VERSION 5.7 ;
  NOWIREEXTENSIONATPIN ON ;
  DIVIDERCHAR "/" ;
  BUSBITCHARS "[]" ;
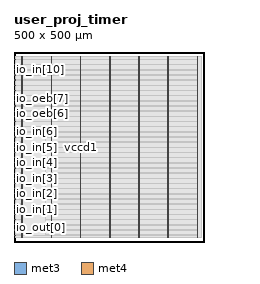
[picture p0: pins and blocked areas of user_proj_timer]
MACRO user_proj_timer
  CLASS BLOCK ;
  FOREIGN user_proj_timer ;
  ORIGIN 0.000 0.000 ;
  SIZE 500.000 BY 500.000 ;
  PIN io_in[0]
    DIRECTION INPUT ;
    USE SIGNAL ;
    ANTENNAGATEAREA 0.126000 ;
    PORT
      LAYER met3 ;
        RECT 0.000 44.920 4.000 45.520 ;
    END
  END io_in[0]
  PIN io_in[10]
    DIRECTION INPUT ;
    USE SIGNAL ;
    PORT
      LAYER met3 ;
        RECT 0.000 452.920 4.000 453.520 ;
    END
  END io_in[10]
  PIN io_in[1]
    DIRECTION INPUT ;
    USE SIGNAL ;
    ANTENNAGATEAREA 0.196500 ;
    PORT
      LAYER met3 ;
        RECT 0.000 85.720 4.000 86.320 ;
    END
  END io_in[1]
  PIN io_in[2]
    DIRECTION INPUT ;
    USE SIGNAL ;
    PORT
      LAYER met3 ;
        RECT 0.000 126.520 4.000 127.120 ;
    END
  END io_in[2]
  PIN io_in[3]
    DIRECTION INPUT ;
    USE SIGNAL ;
    PORT
      LAYER met3 ;
        RECT 0.000 167.320 4.000 167.920 ;
    END
  END io_in[3]
  PIN io_in[4]
    DIRECTION INPUT ;
    USE SIGNAL ;
    PORT
      LAYER met3 ;
        RECT 0.000 208.120 4.000 208.720 ;
    END
  END io_in[4]
  PIN io_in[5]
    DIRECTION INPUT ;
    USE SIGNAL ;
    PORT
      LAYER met3 ;
        RECT 0.000 248.920 4.000 249.520 ;
    END
  END io_in[5]
  PIN io_in[6]
    DIRECTION INPUT ;
    USE SIGNAL ;
    PORT
      LAYER met3 ;
        RECT 0.000 289.720 4.000 290.320 ;
    END
  END io_in[6]
  PIN io_in[7]
    DIRECTION INPUT ;
    USE SIGNAL ;
    PORT
      LAYER met3 ;
        RECT 0.000 330.520 4.000 331.120 ;
    END
  END io_in[7]
  PIN io_in[8]
    DIRECTION INPUT ;
    USE SIGNAL ;
    PORT
      LAYER met3 ;
        RECT 0.000 371.320 4.000 371.920 ;
    END
  END io_in[8]
  PIN io_in[9]
    DIRECTION INPUT ;
    USE SIGNAL ;
    PORT
      LAYER met3 ;
        RECT 0.000 412.120 4.000 412.720 ;
    END
  END io_in[9]
  PIN io_oeb[0]
    DIRECTION OUTPUT ;
    USE SIGNAL ;
    PORT
      LAYER met3 ;
        RECT 0.000 72.120 4.000 72.720 ;
    END
  END io_oeb[0]
  PIN io_oeb[10]
    DIRECTION OUTPUT ;
    USE SIGNAL ;
    PORT
      LAYER met3 ;
        RECT 0.000 480.120 4.000 480.720 ;
    END
  END io_oeb[10]
  PIN io_oeb[1]
    DIRECTION OUTPUT ;
    USE SIGNAL ;
    PORT
      LAYER met3 ;
        RECT 0.000 112.920 4.000 113.520 ;
    END
  END io_oeb[1]
  PIN io_oeb[2]
    DIRECTION OUTPUT ;
    USE SIGNAL ;
    PORT
      LAYER met3 ;
        RECT 0.000 153.720 4.000 154.320 ;
    END
  END io_oeb[2]
  PIN io_oeb[3]
    DIRECTION OUTPUT ;
    USE SIGNAL ;
    PORT
      LAYER met3 ;
        RECT 0.000 194.520 4.000 195.120 ;
    END
  END io_oeb[3]
  PIN io_oeb[4]
    DIRECTION OUTPUT ;
    USE SIGNAL ;
    PORT
      LAYER met3 ;
        RECT 0.000 235.320 4.000 235.920 ;
    END
  END io_oeb[4]
  PIN io_oeb[5]
    DIRECTION OUTPUT ;
    USE SIGNAL ;
    PORT
      LAYER met3 ;
        RECT 0.000 276.120 4.000 276.720 ;
    END
  END io_oeb[5]
  PIN io_oeb[6]
    DIRECTION OUTPUT ;
    USE SIGNAL ;
    PORT
      LAYER met3 ;
        RECT 0.000 316.920 4.000 317.520 ;
    END
  END io_oeb[6]
  PIN io_oeb[7]
    DIRECTION OUTPUT ;
    USE SIGNAL ;
    PORT
      LAYER met3 ;
        RECT 0.000 357.720 4.000 358.320 ;
    END
  END io_oeb[7]
  PIN io_oeb[8]
    DIRECTION OUTPUT ;
    USE SIGNAL ;
    PORT
      LAYER met3 ;
        RECT 0.000 398.520 4.000 399.120 ;
    END
  END io_oeb[8]
  PIN io_oeb[9]
    DIRECTION OUTPUT ;
    USE SIGNAL ;
    PORT
      LAYER met3 ;
        RECT 0.000 439.320 4.000 439.920 ;
    END
  END io_oeb[9]
  PIN io_out[0]
    DIRECTION OUTPUT ;
    USE SIGNAL ;
    ANTENNADIFFAREA 0.445500 ;
    PORT
      LAYER met3 ;
        RECT 0.000 58.520 4.000 59.120 ;
    END
  END io_out[0]
  PIN io_out[10]
    DIRECTION OUTPUT ;
    USE SIGNAL ;
    ANTENNADIFFAREA 0.445500 ;
    PORT
      LAYER met3 ;
        RECT 0.000 466.520 4.000 467.120 ;
    END
  END io_out[10]
  PIN io_out[1]
    DIRECTION OUTPUT ;
    USE SIGNAL ;
    ANTENNADIFFAREA 0.445500 ;
    PORT
      LAYER met3 ;
        RECT 0.000 99.320 4.000 99.920 ;
    END
  END io_out[1]
  PIN io_out[2]
    DIRECTION OUTPUT ;
    USE SIGNAL ;
    ANTENNADIFFAREA 0.445500 ;
    PORT
      LAYER met3 ;
        RECT 0.000 140.120 4.000 140.720 ;
    END
  END io_out[2]
  PIN io_out[3]
    DIRECTION OUTPUT ;
    USE SIGNAL ;
    ANTENNADIFFAREA 0.445500 ;
    PORT
      LAYER met3 ;
        RECT 0.000 180.920 4.000 181.520 ;
    END
  END io_out[3]
  PIN io_out[4]
    DIRECTION OUTPUT ;
    USE SIGNAL ;
    ANTENNADIFFAREA 0.445500 ;
    PORT
      LAYER met3 ;
        RECT 0.000 221.720 4.000 222.320 ;
    END
  END io_out[4]
  PIN io_out[5]
    DIRECTION OUTPUT ;
    USE SIGNAL ;
    ANTENNADIFFAREA 0.445500 ;
    PORT
      LAYER met3 ;
        RECT 0.000 262.520 4.000 263.120 ;
    END
  END io_out[5]
  PIN io_out[6]
    DIRECTION OUTPUT ;
    USE SIGNAL ;
    ANTENNADIFFAREA 0.445500 ;
    PORT
      LAYER met3 ;
        RECT 0.000 303.320 4.000 303.920 ;
    END
  END io_out[6]
  PIN io_out[7]
    DIRECTION OUTPUT ;
    USE SIGNAL ;
    ANTENNADIFFAREA 0.445500 ;
    PORT
      LAYER met3 ;
        RECT 0.000 344.120 4.000 344.720 ;
    END
  END io_out[7]
  PIN io_out[8]
    DIRECTION OUTPUT ;
    USE SIGNAL ;
    ANTENNADIFFAREA 0.445500 ;
    PORT
      LAYER met3 ;
        RECT 0.000 384.920 4.000 385.520 ;
    END
  END io_out[8]
  PIN io_out[9]
    DIRECTION OUTPUT ;
    USE SIGNAL ;
    ANTENNADIFFAREA 0.445500 ;
    PORT
      LAYER met3 ;
        RECT 0.000 425.720 4.000 426.320 ;
    END
  END io_out[9]
  PIN vccd1
    DIRECTION INOUT ;
    USE POWER ;
    PORT
      LAYER met4 ;
        RECT 21.040 10.640 22.640 487.120 ;
    END
    PORT
      LAYER met4 ;
        RECT 174.640 10.640 176.240 487.120 ;
    END
    PORT
      LAYER met4 ;
        RECT 328.240 10.640 329.840 487.120 ;
    END
    PORT
      LAYER met4 ;
        RECT 481.840 10.640 483.440 487.120 ;
    END
  END vccd1
  PIN vssd1
    DIRECTION INOUT ;
    USE GROUND ;
    PORT
      LAYER met4 ;
        RECT 97.840 10.640 99.440 487.120 ;
    END
    PORT
      LAYER met4 ;
        RECT 251.440 10.640 253.040 487.120 ;
    END
    PORT
      LAYER met4 ;
        RECT 405.040 10.640 406.640 487.120 ;
    END
  END vssd1
  PIN wb_clk_i
    DIRECTION INPUT ;
    USE SIGNAL ;
    ANTENNAGATEAREA 0.852000 ;
    ANTENNADIFFAREA 0.434700 ;
    PORT
      LAYER met3 ;
        RECT 0.000 17.720 4.000 18.320 ;
    END
  END wb_clk_i
  PIN wb_rst_i
    DIRECTION INPUT ;
    USE SIGNAL ;
    ANTENNAGATEAREA 0.159000 ;
    PORT
      LAYER met3 ;
        RECT 0.000 31.320 4.000 31.920 ;
    END
  END wb_rst_i
  OBS
      LAYER nwell ;
        RECT 5.330 10.795 494.230 487.070 ;
      LAYER li1 ;
        RECT 5.520 10.795 494.040 486.965 ;
      LAYER met1 ;
        RECT 4.210 10.640 494.040 487.120 ;
      LAYER met2 ;
        RECT 4.230 10.695 483.410 487.065 ;
      LAYER met3 ;
        RECT 3.990 481.120 483.430 487.045 ;
        RECT 4.400 479.720 483.430 481.120 ;
        RECT 3.990 467.520 483.430 479.720 ;
        RECT 4.400 466.120 483.430 467.520 ;
        RECT 3.990 453.920 483.430 466.120 ;
        RECT 4.400 452.520 483.430 453.920 ;
        RECT 3.990 440.320 483.430 452.520 ;
        RECT 4.400 438.920 483.430 440.320 ;
        RECT 3.990 426.720 483.430 438.920 ;
        RECT 4.400 425.320 483.430 426.720 ;
        RECT 3.990 413.120 483.430 425.320 ;
        RECT 4.400 411.720 483.430 413.120 ;
        RECT 3.990 399.520 483.430 411.720 ;
        RECT 4.400 398.120 483.430 399.520 ;
        RECT 3.990 385.920 483.430 398.120 ;
        RECT 4.400 384.520 483.430 385.920 ;
        RECT 3.990 372.320 483.430 384.520 ;
        RECT 4.400 370.920 483.430 372.320 ;
        RECT 3.990 358.720 483.430 370.920 ;
        RECT 4.400 357.320 483.430 358.720 ;
        RECT 3.990 345.120 483.430 357.320 ;
        RECT 4.400 343.720 483.430 345.120 ;
        RECT 3.990 331.520 483.430 343.720 ;
        RECT 4.400 330.120 483.430 331.520 ;
        RECT 3.990 317.920 483.430 330.120 ;
        RECT 4.400 316.520 483.430 317.920 ;
        RECT 3.990 304.320 483.430 316.520 ;
        RECT 4.400 302.920 483.430 304.320 ;
        RECT 3.990 290.720 483.430 302.920 ;
        RECT 4.400 289.320 483.430 290.720 ;
        RECT 3.990 277.120 483.430 289.320 ;
        RECT 4.400 275.720 483.430 277.120 ;
        RECT 3.990 263.520 483.430 275.720 ;
        RECT 4.400 262.120 483.430 263.520 ;
        RECT 3.990 249.920 483.430 262.120 ;
        RECT 4.400 248.520 483.430 249.920 ;
        RECT 3.990 236.320 483.430 248.520 ;
        RECT 4.400 234.920 483.430 236.320 ;
        RECT 3.990 222.720 483.430 234.920 ;
        RECT 4.400 221.320 483.430 222.720 ;
        RECT 3.990 209.120 483.430 221.320 ;
        RECT 4.400 207.720 483.430 209.120 ;
        RECT 3.990 195.520 483.430 207.720 ;
        RECT 4.400 194.120 483.430 195.520 ;
        RECT 3.990 181.920 483.430 194.120 ;
        RECT 4.400 180.520 483.430 181.920 ;
        RECT 3.990 168.320 483.430 180.520 ;
        RECT 4.400 166.920 483.430 168.320 ;
        RECT 3.990 154.720 483.430 166.920 ;
        RECT 4.400 153.320 483.430 154.720 ;
        RECT 3.990 141.120 483.430 153.320 ;
        RECT 4.400 139.720 483.430 141.120 ;
        RECT 3.990 127.520 483.430 139.720 ;
        RECT 4.400 126.120 483.430 127.520 ;
        RECT 3.990 113.920 483.430 126.120 ;
        RECT 4.400 112.520 483.430 113.920 ;
        RECT 3.990 100.320 483.430 112.520 ;
        RECT 4.400 98.920 483.430 100.320 ;
        RECT 3.990 86.720 483.430 98.920 ;
        RECT 4.400 85.320 483.430 86.720 ;
        RECT 3.990 73.120 483.430 85.320 ;
        RECT 4.400 71.720 483.430 73.120 ;
        RECT 3.990 59.520 483.430 71.720 ;
        RECT 4.400 58.120 483.430 59.520 ;
        RECT 3.990 45.920 483.430 58.120 ;
        RECT 4.400 44.520 483.430 45.920 ;
        RECT 3.990 32.320 483.430 44.520 ;
        RECT 4.400 30.920 483.430 32.320 ;
        RECT 3.990 18.720 483.430 30.920 ;
        RECT 4.400 17.320 483.430 18.720 ;
        RECT 3.990 10.715 483.430 17.320 ;
      LAYER met4 ;
        RECT 19.615 17.855 20.640 277.265 ;
        RECT 23.040 17.855 83.425 277.265 ;
  END
END user_proj_timer
END LIBRARY

